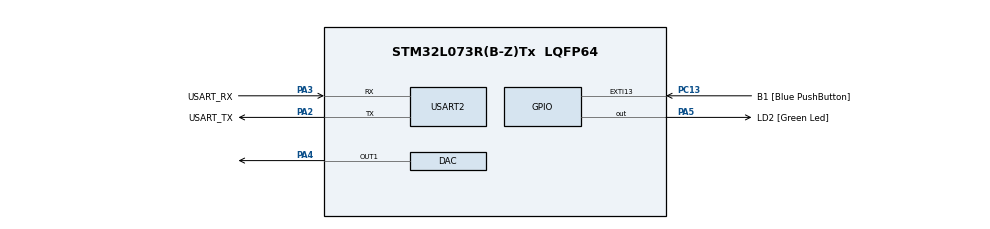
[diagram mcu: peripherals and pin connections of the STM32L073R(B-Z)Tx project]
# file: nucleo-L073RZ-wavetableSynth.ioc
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DAC.DAC_Trigger=DAC_TRIGGER_T6_TRGO
DAC.TriangleAmplitude=DAC_TRIANGLEAMPLITUDE_4095
DAC.WaveGeneration=TriangleWaveGeneration
Mcu.Family=STM32L0
Mcu.Name=STM32L073R(B-Z)Tx
Mcu.Package=LQFP64
NVIC.EXTI4_15_IRQn=true\:0\:0\:false\:false\:true\:true\:true\:true
PA13.GPIO_Label=TMS
PA13.Mode=Serial_Wire
PA13.Signal=SYS_SWDIO
PA14.GPIO_Label=TCK
PA14.Mode=Serial_Wire
PA14.Signal=SYS_SWCLK
PA2.GPIO_Label=USART_TX
PA2.Mode=Asynchronous
PA2.Signal=USART2_TX
PA3.GPIO_Label=USART_RX
PA3.Mode=Asynchronous
PA3.Signal=USART2_RX
PA4.Signal=COMP_DAC1_group
PA5.GPIO_Label=LD2 [Green Led]
PA5.Signal=GPIO_Output
PC13.GPIO_Label=B1 [Blue PushButton]
PC13.GPIO_ModeDefaultEXTI=GPIO_MODE_IT_FALLING
PC13.Signal=GPXTI13
PC14-OSC32_IN.Mode=LSE-External-Oscillator
PC14-OSC32_IN.Signal=RCC_OSC32_IN
PC15-OSC32_OUT.Mode=LSE-External-Oscillator
PC15-OSC32_OUT.Signal=RCC_OSC32_OUT
PH0-OSC_IN.GPIO_Label=MCO
PH0-OSC_IN.Mode=HSE-External-Clock-Source
PH0-OSC_IN.Signal=RCC_OSC_IN
ProjectManager.HeapSize=0x200
ProjectManager.StackSize=0x400
ProjectManager.TargetToolchain=STM32CubeIDE
RCC.AHBFreq_Value=16000000
RCC.APB1Freq_Value=16000000
RCC.APB1TimFreq_Value=16000000
RCC.APB2Freq_Value=16000000
RCC.APB2TimFreq_Value=16000000
RCC.HCLKFreq_Value=16000000
RCC.HSE_VALUE=8000000
RCC.HSI16_VALUE=16000000
RCC.HSI48_VALUE=48000000
RCC.HSI_VALUE=16000000
RCC.MSI_VALUE=2097000
RCC.PLLMUL=RCC_PLLMUL_4
RCC.PLLSourceVirtual=RCC_PLLSOURCE_HSE
RCC.SYSCLKFreq_VALUE=16000000
RCC.SYSCLKSource=RCC_SYSCLKSOURCE_PLLCLK
RCC.VCOOutputFreq_Value=32000000
SH.COMP_DAC1_group.0=DAC_OUT1,DAC_OUT1
TIM6.AutoReloadPreload=TIM_AUTORELOAD_PRELOAD_ENABLE
TIM6.Period=4
TIM6.TIM_MasterOutputTrigger=TIM_TRGO_UPDATE
USART2.VirtualMode-Asynchronous=VM_ASYNC
VP_TIM6_VS_ClockSourceINT.Mode=Enable_Timer
board=NUCLEO-L073RZ

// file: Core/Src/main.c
/* USER CODE BEGIN Header */
/**
 ******************************************************************************
 * @file           : main.c
 * @brief          : Main program body
 ******************************************************************************
 * @attention
 *
 * Copyright (c) 2024 STMicroelectronics.
 * All rights reserved.
 *
 * This software is licensed under terms that can be found in the LICENSE file
 * in the root directory of this software component.
 * If no LICENSE file comes with this software, it is provided AS-IS.
 *
 ******************************************************************************
 */
/* USER CODE END Header */
#include "main.h"

/* USER CODE BEGIN Includes */
#include <stdio.h>
#include <string.h>
#include <math.h>
/* USER CODE END Includes */

/* USER CODE BEGIN PD */

#define UART_BUFFER_SIZE 100

/* USER CODE END PD */

DAC_HandleTypeDef hdac;
DMA_HandleTypeDef hdma_dac_ch1;

TIM_HandleTypeDef htim6;

UART_HandleTypeDef huart2;

/* USER CODE BEGIN PV */

uint16_t button_counter = 0; // cyclic counter for user button edges

/* USER CODE END PV */

void SystemClock_Config(void);
static void MX_GPIO_Init(void);
static void MX_DMA_Init(void);
static void MX_USART2_UART_Init(void);
static void MX_DAC_Init(void);
static void MX_TIM6_Init(void);

int main(void)
{
  /* USER CODE BEGIN 1 */
	uint8_t uart_buf[UART_BUFFER_SIZE];
  /* USER CODE END 1 */

  /* MCU Configuration--------------------------------------------------------*/

  /* Reset of all peripherals, Initializes the Flash interface and the Systick. */
  HAL_Init();

  /* Configure the system clock */
  SystemClock_Config();

  /* Initialize all configured peripherals */
  MX_GPIO_Init();
  MX_DMA_Init();
  MX_USART2_UART_Init();
  MX_DAC_Init();
  MX_TIM6_Init();
  /* USER CODE BEGIN 2 */

	strcpy((char*) uart_buf,
			"The peripherals have been configured successfully.\r\n");
	HAL_UART_Transmit(&huart2, uart_buf, strlen((char*) uart_buf),
	HAL_MAX_DELAY);

	HAL_TIM_Base_Start(&htim6);
	//HAL_TIM_Base_Start_IT(&htim6)

	//HAL_DAC_Start(&hdac, DAC_CHANNEL_1);

	uint16_t dac_dma_buffer[882]; // wave to play
	for (int n = 0; n < 882; n++) { // generates a 12-bit sine wave, 1 period
		double sinn = sin(4 * (2 * M_PI * n) / 882);
		dac_dma_buffer[n] = (uint16_t) ((sinn + 1.15) * (3080 / 2));
	}

	HAL_DAC_Start_DMA(&hdac, DAC_CHANNEL_1, (uint32_t*)dac_dma_buffer, 882, DAC_ALIGN_12B_R);

  /* USER CODE END 2 */

  /* Infinite loop */
	while (1) {

	}
}

void SystemClock_Config(void)
{
  RCC_OscInitTypeDef RCC_OscInitStruct = {0};
  RCC_ClkInitTypeDef RCC_ClkInitStruct = {0};
  RCC_PeriphCLKInitTypeDef PeriphClkInit = {0};

  /** Configure the main internal regulator output voltage
  */
  __HAL_PWR_VOLTAGESCALING_CONFIG(PWR_REGULATOR_VOLTAGE_SCALE1);

  /** Initializes the RCC Oscillators according to the specified parameters
  * in the RCC_OscInitTypeDef structure.
  */
  RCC_OscInitStruct.OscillatorType = RCC_OSCILLATORTYPE_HSI;
  RCC_OscInitStruct.HSIState = RCC_HSI_ON;
  RCC_OscInitStruct.HSICalibrationValue = RCC_HSICALIBRATION_DEFAULT;
  RCC_OscInitStruct.PLL.PLLState = RCC_PLL_ON;
  RCC_OscInitStruct.PLL.PLLSource = RCC_PLLSOURCE_HSI;
  RCC_OscInitStruct.PLL.PLLMUL = RCC_PLLMUL_3;
  RCC_OscInitStruct.PLL.PLLDIV = RCC_PLLDIV_2;
  if (HAL_RCC_OscConfig(&RCC_OscInitStruct) != HAL_OK)
  {
    Error_Handler();
  }

  /** Initializes the CPU, AHB and APB buses clocks
  */
  RCC_ClkInitStruct.ClockType = RCC_CLOCKTYPE_HCLK|RCC_CLOCKTYPE_SYSCLK
                              |RCC_CLOCKTYPE_PCLK1|RCC_CLOCKTYPE_PCLK2;
  RCC_ClkInitStruct.SYSCLKSource = RCC_SYSCLKSOURCE_PLLCLK;
  RCC_ClkInitStruct.AHBCLKDivider = RCC_SYSCLK_DIV2;
  RCC_ClkInitStruct.APB1CLKDivider = RCC_HCLK_DIV1;
  RCC_ClkInitStruct.APB2CLKDivider = RCC_HCLK_DIV1;

  if (HAL_RCC_ClockConfig(&RCC_ClkInitStruct, FLASH_LATENCY_0) != HAL_OK)
  {
    Error_Handler();
  }
  PeriphClkInit.PeriphClockSelection = RCC_PERIPHCLK_USART2;
  PeriphClkInit.Usart2ClockSelection = RCC_USART2CLKSOURCE_PCLK1;
  if (HAL_RCCEx_PeriphCLKConfig(&PeriphClkInit) != HAL_OK)
  {
    Error_Handler();
  }
}

static void MX_DAC_Init(void)
{

  DAC_ChannelConfTypeDef sConfig = {0};

  /** DAC Initialization
  */
  hdac.Instance = DAC;
  if (HAL_DAC_Init(&hdac) != HAL_OK)
  {
    Error_Handler();
  }

  /** DAC channel OUT1 config
  */
  sConfig.DAC_Trigger = DAC_TRIGGER_T6_TRGO;
  sConfig.DAC_OutputBuffer = DAC_OUTPUTBUFFER_ENABLE;
  if (HAL_DAC_ConfigChannel(&hdac, &sConfig, DAC_CHANNEL_1) != HAL_OK)
  {
    Error_Handler();
  }

}

static void MX_TIM6_Init(void)
{

  TIM_MasterConfigTypeDef sMasterConfig = {0};

  htim6.Instance = TIM6;
  htim6.Init.Prescaler = 0;
  htim6.Init.CounterMode = TIM_COUNTERMODE_UP;
  htim6.Init.Period = 181;
  htim6.Init.AutoReloadPreload = TIM_AUTORELOAD_PRELOAD_ENABLE;
  if (HAL_TIM_Base_Init(&htim6) != HAL_OK)
  {
    Error_Handler();
  }
  sMasterConfig.MasterOutputTrigger = TIM_TRGO_UPDATE;
  sMasterConfig.MasterSlaveMode = TIM_MASTERSLAVEMODE_DISABLE;
  if (HAL_TIMEx_MasterConfigSynchronization(&htim6, &sMasterConfig) != HAL_OK)
  {
    Error_Handler();
  }

}

static void MX_USART2_UART_Init(void)
{

  huart2.Instance = USART2;
  huart2.Init.BaudRate = 115200;
  huart2.Init.WordLength = UART_WORDLENGTH_8B;
  huart2.Init.StopBits = UART_STOPBITS_1;
  huart2.Init.Parity = UART_PARITY_NONE;
  huart2.Init.Mode = UART_MODE_TX_RX;
  huart2.Init.HwFlowCtl = UART_HWCONTROL_NONE;
  huart2.Init.OverSampling = UART_OVERSAMPLING_16;
  huart2.Init.OneBitSampling = UART_ONE_BIT_SAMPLE_DISABLE;
  huart2.AdvancedInit.AdvFeatureInit = UART_ADVFEATURE_NO_INIT;
  if (HAL_UART_Init(&huart2) != HAL_OK)
  {
    Error_Handler();
  }

}

static void MX_DMA_Init(void)
{

  /* DMA controller clock enable */
  __HAL_RCC_DMA1_CLK_ENABLE();

  /* DMA interrupt init */
  /* DMA1_Channel2_3_IRQn interrupt configuration */
  HAL_NVIC_SetPriority(DMA1_Channel2_3_IRQn, 0, 0);
  HAL_NVIC_EnableIRQ(DMA1_Channel2_3_IRQn);

}

static void MX_GPIO_Init(void)
{
  GPIO_InitTypeDef GPIO_InitStruct = {0};

  /* GPIO Ports Clock Enable */
  __HAL_RCC_GPIOC_CLK_ENABLE();
  __HAL_RCC_GPIOH_CLK_ENABLE();
  __HAL_RCC_GPIOA_CLK_ENABLE();

  /*Configure GPIO pin Output Level */
  HAL_GPIO_WritePin(LD2_GPIO_Port, LD2_Pin, GPIO_PIN_RESET);

  /*Configure GPIO pin : B1_Pin */
  GPIO_InitStruct.Pin = B1_Pin;
  GPIO_InitStruct.Mode = GPIO_MODE_IT_FALLING;
  GPIO_InitStruct.Pull = GPIO_NOPULL;
  HAL_GPIO_Init(B1_GPIO_Port, &GPIO_InitStruct);

  /*Configure GPIO pin : LD2_Pin */
  GPIO_InitStruct.Pin = LD2_Pin;
  GPIO_InitStruct.Mode = GPIO_MODE_OUTPUT_PP;
  GPIO_InitStruct.Pull = GPIO_NOPULL;
  GPIO_InitStruct.Speed = GPIO_SPEED_FREQ_LOW;
  HAL_GPIO_Init(LD2_GPIO_Port, &GPIO_InitStruct);

  /* EXTI interrupt init*/
  HAL_NVIC_SetPriority(EXTI4_15_IRQn, 0, 0);
  HAL_NVIC_EnableIRQ(EXTI4_15_IRQn);

}

/* USER CODE BEGIN 4 */

void HAL_GPIO_EXTI_Callback(uint16_t GPIO_Pin) {
	HAL_GPIO_TogglePin(GPIOA, GPIO_PIN_5);
	if (GPIO_Pin == B1_Pin) {
		button_counter = (button_counter + 1) % 7;
		//__HAL_TIM_SET_PRESCALER(&htim6,button_counter);
		__HAL_TIM_SET_AUTORELOAD(&htim6, button_counter + 1);
	}

}

/* USER CODE END 4 */

void Error_Handler(void)
{
	__disable_irq();
	while (1) {
	}
}
